VERSION 5.7 ;
BUSBITCHARS "[]" ;
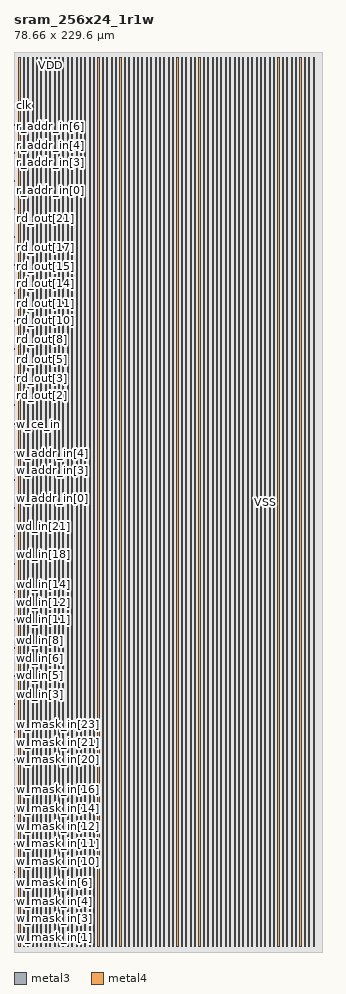
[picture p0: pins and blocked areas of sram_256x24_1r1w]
MACRO sram_256x24_1r1w
  FOREIGN sram_256x24_1r1w 0 0 ;
  SYMMETRY X Y R90 ;
  SIZE 78.660 BY 229.600 ;
  CLASS BLOCK ;
  PIN w_mask_in[0]
    DIRECTION INPUT ;
    USE SIGNAL ;
    SHAPE ABUTMENT ;
    PORT
      LAYER metal3 ;
      RECT 0.000 1.365 0.070 1.435 ;
    END
  END w_mask_in[0]
  PIN w_mask_in[1]
    DIRECTION INPUT ;
    USE SIGNAL ;
    SHAPE ABUTMENT ;
    PORT
      LAYER metal3 ;
      RECT 0.000 3.745 0.070 3.815 ;
    END
  END w_mask_in[1]
  PIN w_mask_in[2]
    DIRECTION INPUT ;
    USE SIGNAL ;
    SHAPE ABUTMENT ;
    PORT
      LAYER metal3 ;
      RECT 0.000 6.125 0.070 6.195 ;
    END
  END w_mask_in[2]
  PIN w_mask_in[3]
    DIRECTION INPUT ;
    USE SIGNAL ;
    SHAPE ABUTMENT ;
    PORT
      LAYER metal3 ;
      RECT 0.000 8.505 0.070 8.575 ;
    END
  END w_mask_in[3]
  PIN w_mask_in[4]
    DIRECTION INPUT ;
    USE SIGNAL ;
    SHAPE ABUTMENT ;
    PORT
      LAYER metal3 ;
      RECT 0.000 10.885 0.070 10.955 ;
    END
  END w_mask_in[4]
  PIN w_mask_in[5]
    DIRECTION INPUT ;
    USE SIGNAL ;
    SHAPE ABUTMENT ;
    PORT
      LAYER metal3 ;
      RECT 0.000 13.265 0.070 13.335 ;
    END
  END w_mask_in[5]
  PIN w_mask_in[6]
    DIRECTION INPUT ;
    USE SIGNAL ;
    SHAPE ABUTMENT ;
    PORT
      LAYER metal3 ;
      RECT 0.000 15.645 0.070 15.715 ;
    END
  END w_mask_in[6]
  PIN w_mask_in[7]
    DIRECTION INPUT ;
    USE SIGNAL ;
    SHAPE ABUTMENT ;
    PORT
      LAYER metal3 ;
      RECT 0.000 18.025 0.070 18.095 ;
    END
  END w_mask_in[7]
  PIN w_mask_in[8]
    DIRECTION INPUT ;
    USE SIGNAL ;
    SHAPE ABUTMENT ;
    PORT
      LAYER metal3 ;
      RECT 0.000 20.405 0.070 20.475 ;
    END
  END w_mask_in[8]
  PIN w_mask_in[9]
    DIRECTION INPUT ;
    USE SIGNAL ;
    SHAPE ABUTMENT ;
    PORT
      LAYER metal3 ;
      RECT 0.000 22.785 0.070 22.855 ;
    END
  END w_mask_in[9]
  PIN w_mask_in[10]
    DIRECTION INPUT ;
    USE SIGNAL ;
    SHAPE ABUTMENT ;
    PORT
      LAYER metal3 ;
      RECT 0.000 25.165 0.070 25.235 ;
    END
  END w_mask_in[10]
  PIN w_mask_in[11]
    DIRECTION INPUT ;
    USE SIGNAL ;
    SHAPE ABUTMENT ;
    PORT
      LAYER metal3 ;
      RECT 0.000 27.545 0.070 27.615 ;
    END
  END w_mask_in[11]
  PIN w_mask_in[12]
    DIRECTION INPUT ;
    USE SIGNAL ;
    SHAPE ABUTMENT ;
    PORT
      LAYER metal3 ;
      RECT 0.000 29.925 0.070 29.995 ;
    END
  END w_mask_in[12]
  PIN w_mask_in[13]
    DIRECTION INPUT ;
    USE SIGNAL ;
    SHAPE ABUTMENT ;
    PORT
      LAYER metal3 ;
      RECT 0.000 32.305 0.070 32.375 ;
    END
  END w_mask_in[13]
  PIN w_mask_in[14]
    DIRECTION INPUT ;
    USE SIGNAL ;
    SHAPE ABUTMENT ;
    PORT
      LAYER metal3 ;
      RECT 0.000 34.685 0.070 34.755 ;
    END
  END w_mask_in[14]
  PIN w_mask_in[15]
    DIRECTION INPUT ;
    USE SIGNAL ;
    SHAPE ABUTMENT ;
    PORT
      LAYER metal3 ;
      RECT 0.000 37.065 0.070 37.135 ;
    END
  END w_mask_in[15]
  PIN w_mask_in[16]
    DIRECTION INPUT ;
    USE SIGNAL ;
    SHAPE ABUTMENT ;
    PORT
      LAYER metal3 ;
      RECT 0.000 39.445 0.070 39.515 ;
    END
  END w_mask_in[16]
  PIN w_mask_in[17]
    DIRECTION INPUT ;
    USE SIGNAL ;
    SHAPE ABUTMENT ;
    PORT
      LAYER metal3 ;
      RECT 0.000 41.825 0.070 41.895 ;
    END
  END w_mask_in[17]
  PIN w_mask_in[18]
    DIRECTION INPUT ;
    USE SIGNAL ;
    SHAPE ABUTMENT ;
    PORT
      LAYER metal3 ;
      RECT 0.000 44.205 0.070 44.275 ;
    END
  END w_mask_in[18]
  PIN w_mask_in[19]
    DIRECTION INPUT ;
    USE SIGNAL ;
    SHAPE ABUTMENT ;
    PORT
      LAYER metal3 ;
      RECT 0.000 46.585 0.070 46.655 ;
    END
  END w_mask_in[19]
  PIN w_mask_in[20]
    DIRECTION INPUT ;
    USE SIGNAL ;
    SHAPE ABUTMENT ;
    PORT
      LAYER metal3 ;
      RECT 0.000 48.965 0.070 49.035 ;
    END
  END w_mask_in[20]
  PIN w_mask_in[21]
    DIRECTION INPUT ;
    USE SIGNAL ;
    SHAPE ABUTMENT ;
    PORT
      LAYER metal3 ;
      RECT 0.000 51.345 0.070 51.415 ;
    END
  END w_mask_in[21]
  PIN w_mask_in[22]
    DIRECTION INPUT ;
    USE SIGNAL ;
    SHAPE ABUTMENT ;
    PORT
      LAYER metal3 ;
      RECT 0.000 53.725 0.070 53.795 ;
    END
  END w_mask_in[22]
  PIN w_mask_in[23]
    DIRECTION INPUT ;
    USE SIGNAL ;
    SHAPE ABUTMENT ;
    PORT
      LAYER metal3 ;
      RECT 0.000 56.105 0.070 56.175 ;
    END
  END w_mask_in[23]
  PIN wd_in[0]
    DIRECTION INPUT ;
    USE SIGNAL ;
    SHAPE ABUTMENT ;
    PORT
      LAYER metal3 ;
      RECT 0.000 58.485 0.070 58.555 ;
    END
  END wd_in[0]
  PIN wd_in[1]
    DIRECTION INPUT ;
    USE SIGNAL ;
    SHAPE ABUTMENT ;
    PORT
      LAYER metal3 ;
      RECT 0.000 60.865 0.070 60.935 ;
    END
  END wd_in[1]
  PIN wd_in[2]
    DIRECTION INPUT ;
    USE SIGNAL ;
    SHAPE ABUTMENT ;
    PORT
      LAYER metal3 ;
      RECT 0.000 63.245 0.070 63.315 ;
    END
  END wd_in[2]
  PIN wd_in[3]
    DIRECTION INPUT ;
    USE SIGNAL ;
    SHAPE ABUTMENT ;
    PORT
      LAYER metal3 ;
      RECT 0.000 65.625 0.070 65.695 ;
    END
  END wd_in[3]
  PIN wd_in[4]
    DIRECTION INPUT ;
    USE SIGNAL ;
    SHAPE ABUTMENT ;
    PORT
      LAYER metal3 ;
      RECT 0.000 68.005 0.070 68.075 ;
    END
  END wd_in[4]
  PIN wd_in[5]
    DIRECTION INPUT ;
    USE SIGNAL ;
    SHAPE ABUTMENT ;
    PORT
      LAYER metal3 ;
      RECT 0.000 70.385 0.070 70.455 ;
    END
  END wd_in[5]
  PIN wd_in[6]
    DIRECTION INPUT ;
    USE SIGNAL ;
    SHAPE ABUTMENT ;
    PORT
      LAYER metal3 ;
      RECT 0.000 72.765 0.070 72.835 ;
    END
  END wd_in[6]
  PIN wd_in[7]
    DIRECTION INPUT ;
    USE SIGNAL ;
    SHAPE ABUTMENT ;
    PORT
      LAYER metal3 ;
      RECT 0.000 75.145 0.070 75.215 ;
    END
  END wd_in[7]
  PIN wd_in[8]
    DIRECTION INPUT ;
    USE SIGNAL ;
    SHAPE ABUTMENT ;
    PORT
      LAYER metal3 ;
      RECT 0.000 77.525 0.070 77.595 ;
    END
  END wd_in[8]
  PIN wd_in[9]
    DIRECTION INPUT ;
    USE SIGNAL ;
    SHAPE ABUTMENT ;
    PORT
      LAYER metal3 ;
      RECT 0.000 79.905 0.070 79.975 ;
    END
  END wd_in[9]
  PIN wd_in[10]
    DIRECTION INPUT ;
    USE SIGNAL ;
    SHAPE ABUTMENT ;
    PORT
      LAYER metal3 ;
      RECT 0.000 82.285 0.070 82.355 ;
    END
  END wd_in[10]
  PIN wd_in[11]
    DIRECTION INPUT ;
    USE SIGNAL ;
    SHAPE ABUTMENT ;
    PORT
      LAYER metal3 ;
      RECT 0.000 84.665 0.070 84.735 ;
    END
  END wd_in[11]
  PIN wd_in[12]
    DIRECTION INPUT ;
    USE SIGNAL ;
    SHAPE ABUTMENT ;
    PORT
      LAYER metal3 ;
      RECT 0.000 87.045 0.070 87.115 ;
    END
  END wd_in[12]
  PIN wd_in[13]
    DIRECTION INPUT ;
    USE SIGNAL ;
    SHAPE ABUTMENT ;
    PORT
      LAYER metal3 ;
      RECT 0.000 89.425 0.070 89.495 ;
    END
  END wd_in[13]
  PIN wd_in[14]
    DIRECTION INPUT ;
    USE SIGNAL ;
    SHAPE ABUTMENT ;
    PORT
      LAYER metal3 ;
      RECT 0.000 91.805 0.070 91.875 ;
    END
  END wd_in[14]
  PIN wd_in[15]
    DIRECTION INPUT ;
    USE SIGNAL ;
    SHAPE ABUTMENT ;
    PORT
      LAYER metal3 ;
      RECT 0.000 94.185 0.070 94.255 ;
    END
  END wd_in[15]
  PIN wd_in[16]
    DIRECTION INPUT ;
    USE SIGNAL ;
    SHAPE ABUTMENT ;
    PORT
      LAYER metal3 ;
      RECT 0.000 96.565 0.070 96.635 ;
    END
  END wd_in[16]
  PIN wd_in[17]
    DIRECTION INPUT ;
    USE SIGNAL ;
    SHAPE ABUTMENT ;
    PORT
      LAYER metal3 ;
      RECT 0.000 98.945 0.070 99.015 ;
    END
  END wd_in[17]
  PIN wd_in[18]
    DIRECTION INPUT ;
    USE SIGNAL ;
    SHAPE ABUTMENT ;
    PORT
      LAYER metal3 ;
      RECT 0.000 101.325 0.070 101.395 ;
    END
  END wd_in[18]
  PIN wd_in[19]
    DIRECTION INPUT ;
    USE SIGNAL ;
    SHAPE ABUTMENT ;
    PORT
      LAYER metal3 ;
      RECT 0.000 103.705 0.070 103.775 ;
    END
  END wd_in[19]
  PIN wd_in[20]
    DIRECTION INPUT ;
    USE SIGNAL ;
    SHAPE ABUTMENT ;
    PORT
      LAYER metal3 ;
      RECT 0.000 106.085 0.070 106.155 ;
    END
  END wd_in[20]
  PIN wd_in[21]
    DIRECTION INPUT ;
    USE SIGNAL ;
    SHAPE ABUTMENT ;
    PORT
      LAYER metal3 ;
      RECT 0.000 108.465 0.070 108.535 ;
    END
  END wd_in[21]
  PIN wd_in[22]
    DIRECTION INPUT ;
    USE SIGNAL ;
    SHAPE ABUTMENT ;
    PORT
      LAYER metal3 ;
      RECT 0.000 110.845 0.070 110.915 ;
    END
  END wd_in[22]
  PIN wd_in[23]
    DIRECTION INPUT ;
    USE SIGNAL ;
    SHAPE ABUTMENT ;
    PORT
      LAYER metal3 ;
      RECT 0.000 113.225 0.070 113.295 ;
    END
  END wd_in[23]
  PIN w_addr_in[0]
    DIRECTION INPUT ;
    USE SIGNAL ;
    SHAPE ABUTMENT ;
    PORT
      LAYER metal3 ;
      RECT 0.000 115.605 0.070 115.675 ;
    END
  END w_addr_in[0]
  PIN w_addr_in[1]
    DIRECTION INPUT ;
    USE SIGNAL ;
    SHAPE ABUTMENT ;
    PORT
      LAYER metal3 ;
      RECT 0.000 117.985 0.070 118.055 ;
    END
  END w_addr_in[1]
  PIN w_addr_in[2]
    DIRECTION INPUT ;
    USE SIGNAL ;
    SHAPE ABUTMENT ;
    PORT
      LAYER metal3 ;
      RECT 0.000 120.365 0.070 120.435 ;
    END
  END w_addr_in[2]
  PIN w_addr_in[3]
    DIRECTION INPUT ;
    USE SIGNAL ;
    SHAPE ABUTMENT ;
    PORT
      LAYER metal3 ;
      RECT 0.000 122.745 0.070 122.815 ;
    END
  END w_addr_in[3]
  PIN w_addr_in[4]
    DIRECTION INPUT ;
    USE SIGNAL ;
    SHAPE ABUTMENT ;
    PORT
      LAYER metal3 ;
      RECT 0.000 125.125 0.070 125.195 ;
    END
  END w_addr_in[4]
  PIN w_addr_in[5]
    DIRECTION INPUT ;
    USE SIGNAL ;
    SHAPE ABUTMENT ;
    PORT
      LAYER metal3 ;
      RECT 0.000 127.505 0.070 127.575 ;
    END
  END w_addr_in[5]
  PIN w_addr_in[6]
    DIRECTION INPUT ;
    USE SIGNAL ;
    SHAPE ABUTMENT ;
    PORT
      LAYER metal3 ;
      RECT 0.000 129.885 0.070 129.955 ;
    END
  END w_addr_in[6]
  PIN w_addr_in[7]
    DIRECTION INPUT ;
    USE SIGNAL ;
    SHAPE ABUTMENT ;
    PORT
      LAYER metal3 ;
      RECT 0.000 132.265 0.070 132.335 ;
    END
  END w_addr_in[7]
  PIN w_ce_in
    DIRECTION INPUT ;
    USE SIGNAL ;
    SHAPE ABUTMENT ;
    PORT
      LAYER metal3 ;
      RECT 0.000 134.645 0.070 134.715 ;
    END
  END w_ce_in
  PIN rd_out[0]
    DIRECTION OUTPUT ;
    USE SIGNAL ;
    SHAPE ABUTMENT ;
    PORT
      LAYER metal3 ;
      RECT 0.000 137.165 0.070 137.235 ;
    END
  END rd_out[0]
  PIN rd_out[1]
    DIRECTION OUTPUT ;
    USE SIGNAL ;
    SHAPE ABUTMENT ;
    PORT
      LAYER metal3 ;
      RECT 0.000 139.545 0.070 139.615 ;
    END
  END rd_out[1]
  PIN rd_out[2]
    DIRECTION OUTPUT ;
    USE SIGNAL ;
    SHAPE ABUTMENT ;
    PORT
      LAYER metal3 ;
      RECT 0.000 141.925 0.070 141.995 ;
    END
  END rd_out[2]
  PIN rd_out[3]
    DIRECTION OUTPUT ;
    USE SIGNAL ;
    SHAPE ABUTMENT ;
    PORT
      LAYER metal3 ;
      RECT 0.000 144.305 0.070 144.375 ;
    END
  END rd_out[3]
  PIN rd_out[4]
    DIRECTION OUTPUT ;
    USE SIGNAL ;
    SHAPE ABUTMENT ;
    PORT
      LAYER metal3 ;
      RECT 0.000 146.685 0.070 146.755 ;
    END
  END rd_out[4]
  PIN rd_out[5]
    DIRECTION OUTPUT ;
    USE SIGNAL ;
    SHAPE ABUTMENT ;
    PORT
      LAYER metal3 ;
      RECT 0.000 149.065 0.070 149.135 ;
    END
  END rd_out[5]
  PIN rd_out[6]
    DIRECTION OUTPUT ;
    USE SIGNAL ;
    SHAPE ABUTMENT ;
    PORT
      LAYER metal3 ;
      RECT 0.000 151.445 0.070 151.515 ;
    END
  END rd_out[6]
  PIN rd_out[7]
    DIRECTION OUTPUT ;
    USE SIGNAL ;
    SHAPE ABUTMENT ;
    PORT
      LAYER metal3 ;
      RECT 0.000 153.825 0.070 153.895 ;
    END
  END rd_out[7]
  PIN rd_out[8]
    DIRECTION OUTPUT ;
    USE SIGNAL ;
    SHAPE ABUTMENT ;
    PORT
      LAYER metal3 ;
      RECT 0.000 156.205 0.070 156.275 ;
    END
  END rd_out[8]
  PIN rd_out[9]
    DIRECTION OUTPUT ;
    USE SIGNAL ;
    SHAPE ABUTMENT ;
    PORT
      LAYER metal3 ;
      RECT 0.000 158.585 0.070 158.655 ;
    END
  END rd_out[9]
  PIN rd_out[10]
    DIRECTION OUTPUT ;
    USE SIGNAL ;
    SHAPE ABUTMENT ;
    PORT
      LAYER metal3 ;
      RECT 0.000 160.965 0.070 161.035 ;
    END
  END rd_out[10]
  PIN rd_out[11]
    DIRECTION OUTPUT ;
    USE SIGNAL ;
    SHAPE ABUTMENT ;
    PORT
      LAYER metal3 ;
      RECT 0.000 163.345 0.070 163.415 ;
    END
  END rd_out[11]
  PIN rd_out[12]
    DIRECTION OUTPUT ;
    USE SIGNAL ;
    SHAPE ABUTMENT ;
    PORT
      LAYER metal3 ;
      RECT 0.000 165.725 0.070 165.795 ;
    END
  END rd_out[12]
  PIN rd_out[13]
    DIRECTION OUTPUT ;
    USE SIGNAL ;
    SHAPE ABUTMENT ;
    PORT
      LAYER metal3 ;
      RECT 0.000 168.105 0.070 168.175 ;
    END
  END rd_out[13]
  PIN rd_out[14]
    DIRECTION OUTPUT ;
    USE SIGNAL ;
    SHAPE ABUTMENT ;
    PORT
      LAYER metal3 ;
      RECT 0.000 170.485 0.070 170.555 ;
    END
  END rd_out[14]
  PIN rd_out[15]
    DIRECTION OUTPUT ;
    USE SIGNAL ;
    SHAPE ABUTMENT ;
    PORT
      LAYER metal3 ;
      RECT 0.000 172.865 0.070 172.935 ;
    END
  END rd_out[15]
  PIN rd_out[16]
    DIRECTION OUTPUT ;
    USE SIGNAL ;
    SHAPE ABUTMENT ;
    PORT
      LAYER metal3 ;
      RECT 0.000 175.245 0.070 175.315 ;
    END
  END rd_out[16]
  PIN rd_out[17]
    DIRECTION OUTPUT ;
    USE SIGNAL ;
    SHAPE ABUTMENT ;
    PORT
      LAYER metal3 ;
      RECT 0.000 177.625 0.070 177.695 ;
    END
  END rd_out[17]
  PIN rd_out[18]
    DIRECTION OUTPUT ;
    USE SIGNAL ;
    SHAPE ABUTMENT ;
    PORT
      LAYER metal3 ;
      RECT 0.000 180.005 0.070 180.075 ;
    END
  END rd_out[18]
  PIN rd_out[19]
    DIRECTION OUTPUT ;
    USE SIGNAL ;
    SHAPE ABUTMENT ;
    PORT
      LAYER metal3 ;
      RECT 0.000 182.385 0.070 182.455 ;
    END
  END rd_out[19]
  PIN rd_out[20]
    DIRECTION OUTPUT ;
    USE SIGNAL ;
    SHAPE ABUTMENT ;
    PORT
      LAYER metal3 ;
      RECT 0.000 184.765 0.070 184.835 ;
    END
  END rd_out[20]
  PIN rd_out[21]
    DIRECTION OUTPUT ;
    USE SIGNAL ;
    SHAPE ABUTMENT ;
    PORT
      LAYER metal3 ;
      RECT 0.000 187.145 0.070 187.215 ;
    END
  END rd_out[21]
  PIN rd_out[22]
    DIRECTION OUTPUT ;
    USE SIGNAL ;
    SHAPE ABUTMENT ;
    PORT
      LAYER metal3 ;
      RECT 0.000 189.525 0.070 189.595 ;
    END
  END rd_out[22]
  PIN rd_out[23]
    DIRECTION OUTPUT ;
    USE SIGNAL ;
    SHAPE ABUTMENT ;
    PORT
      LAYER metal3 ;
      RECT 0.000 191.905 0.070 191.975 ;
    END
  END rd_out[23]
  PIN r_addr_in[0]
    DIRECTION INPUT ;
    USE SIGNAL ;
    SHAPE ABUTMENT ;
    PORT
      LAYER metal3 ;
      RECT 0.000 194.285 0.070 194.355 ;
    END
  END r_addr_in[0]
  PIN r_addr_in[1]
    DIRECTION INPUT ;
    USE SIGNAL ;
    SHAPE ABUTMENT ;
    PORT
      LAYER metal3 ;
      RECT 0.000 196.665 0.070 196.735 ;
    END
  END r_addr_in[1]
  PIN r_addr_in[2]
    DIRECTION INPUT ;
    USE SIGNAL ;
    SHAPE ABUTMENT ;
    PORT
      LAYER metal3 ;
      RECT 0.000 199.045 0.070 199.115 ;
    END
  END r_addr_in[2]
  PIN r_addr_in[3]
    DIRECTION INPUT ;
    USE SIGNAL ;
    SHAPE ABUTMENT ;
    PORT
      LAYER metal3 ;
      RECT 0.000 201.425 0.070 201.495 ;
    END
  END r_addr_in[3]
  PIN r_addr_in[4]
    DIRECTION INPUT ;
    USE SIGNAL ;
    SHAPE ABUTMENT ;
    PORT
      LAYER metal3 ;
      RECT 0.000 203.805 0.070 203.875 ;
    END
  END r_addr_in[4]
  PIN r_addr_in[5]
    DIRECTION INPUT ;
    USE SIGNAL ;
    SHAPE ABUTMENT ;
    PORT
      LAYER metal3 ;
      RECT 0.000 206.185 0.070 206.255 ;
    END
  END r_addr_in[5]
  PIN r_addr_in[6]
    DIRECTION INPUT ;
    USE SIGNAL ;
    SHAPE ABUTMENT ;
    PORT
      LAYER metal3 ;
      RECT 0.000 208.565 0.070 208.635 ;
    END
  END r_addr_in[6]
  PIN r_addr_in[7]
    DIRECTION INPUT ;
    USE SIGNAL ;
    SHAPE ABUTMENT ;
    PORT
      LAYER metal3 ;
      RECT 0.000 210.945 0.070 211.015 ;
    END
  END r_addr_in[7]
  PIN r_ce_in
    DIRECTION INPUT ;
    USE SIGNAL ;
    SHAPE ABUTMENT ;
    PORT
      LAYER metal3 ;
      RECT 0.000 213.325 0.070 213.395 ;
    END
  END r_ce_in
  PIN clk
    DIRECTION INPUT ;
    USE SIGNAL ;
    SHAPE ABUTMENT ;
    PORT
      LAYER metal3 ;
      RECT 0.000 215.845 0.070 215.915 ;
    END
  END clk
  PIN VSS
    DIRECTION INOUT ;
    USE GROUND ;
    PORT
      LAYER metal4 ;
      RECT 1.260 1.400 1.540 228.200 ;
      RECT 3.500 1.400 3.780 228.200 ;
      RECT 5.740 1.400 6.020 228.200 ;
      RECT 7.980 1.400 8.260 228.200 ;
      RECT 10.220 1.400 10.500 228.200 ;
      RECT 12.460 1.400 12.740 228.200 ;
      RECT 14.700 1.400 14.980 228.200 ;
      RECT 16.940 1.400 17.220 228.200 ;
      RECT 19.180 1.400 19.460 228.200 ;
      RECT 21.420 1.400 21.700 228.200 ;
      RECT 23.660 1.400 23.940 228.200 ;
      RECT 25.900 1.400 26.180 228.200 ;
      RECT 28.140 1.400 28.420 228.200 ;
      RECT 30.380 1.400 30.660 228.200 ;
      RECT 32.620 1.400 32.900 228.200 ;
      RECT 34.860 1.400 35.140 228.200 ;
      RECT 37.100 1.400 37.380 228.200 ;
      RECT 39.340 1.400 39.620 228.200 ;
      RECT 41.580 1.400 41.860 228.200 ;
      RECT 43.820 1.400 44.100 228.200 ;
      RECT 46.060 1.400 46.340 228.200 ;
      RECT 48.300 1.400 48.580 228.200 ;
      RECT 50.540 1.400 50.820 228.200 ;
      RECT 52.780 1.400 53.060 228.200 ;
      RECT 55.020 1.400 55.300 228.200 ;
      RECT 57.260 1.400 57.540 228.200 ;
      RECT 59.500 1.400 59.780 228.200 ;
      RECT 61.740 1.400 62.020 228.200 ;
      RECT 63.980 1.400 64.260 228.200 ;
      RECT 66.220 1.400 66.500 228.200 ;
      RECT 68.460 1.400 68.740 228.200 ;
      RECT 70.700 1.400 70.980 228.200 ;
      RECT 72.940 1.400 73.220 228.200 ;
      RECT 75.180 1.400 75.460 228.200 ;
    END
  END VSS
  PIN VDD
    DIRECTION INOUT ;
    USE POWER ;
    PORT
      LAYER metal4 ;
      RECT 2.380 1.400 2.660 228.200 ;
      RECT 4.620 1.400 4.900 228.200 ;
      RECT 6.860 1.400 7.140 228.200 ;
      RECT 9.100 1.400 9.380 228.200 ;
      RECT 11.340 1.400 11.620 228.200 ;
      RECT 13.580 1.400 13.860 228.200 ;
      RECT 15.820 1.400 16.100 228.200 ;
      RECT 18.060 1.400 18.340 228.200 ;
      RECT 20.300 1.400 20.580 228.200 ;
      RECT 22.540 1.400 22.820 228.200 ;
      RECT 24.780 1.400 25.060 228.200 ;
      RECT 27.020 1.400 27.300 228.200 ;
      RECT 29.260 1.400 29.540 228.200 ;
      RECT 31.500 1.400 31.780 228.200 ;
      RECT 33.740 1.400 34.020 228.200 ;
      RECT 35.980 1.400 36.260 228.200 ;
      RECT 38.220 1.400 38.500 228.200 ;
      RECT 40.460 1.400 40.740 228.200 ;
      RECT 42.700 1.400 42.980 228.200 ;
      RECT 44.940 1.400 45.220 228.200 ;
      RECT 47.180 1.400 47.460 228.200 ;
      RECT 49.420 1.400 49.700 228.200 ;
      RECT 51.660 1.400 51.940 228.200 ;
      RECT 53.900 1.400 54.180 228.200 ;
      RECT 56.140 1.400 56.420 228.200 ;
      RECT 58.380 1.400 58.660 228.200 ;
      RECT 60.620 1.400 60.900 228.200 ;
      RECT 62.860 1.400 63.140 228.200 ;
      RECT 65.100 1.400 65.380 228.200 ;
      RECT 67.340 1.400 67.620 228.200 ;
      RECT 69.580 1.400 69.860 228.200 ;
      RECT 71.820 1.400 72.100 228.200 ;
      RECT 74.060 1.400 74.340 228.200 ;
      RECT 76.300 1.400 76.580 228.200 ;
    END
  END VDD
  OBS
    LAYER metal1 ;
    RECT 0 0 78.660 229.600 ;
    LAYER metal2 ;
    RECT 0 0 78.660 229.600 ;
    LAYER metal3 ;
    RECT 0.070 0 78.660 229.600 ;
    RECT 0 0.000 0.070 1.365 ;
    RECT 0 1.435 0.070 3.745 ;
    RECT 0 3.815 0.070 6.125 ;
    RECT 0 6.195 0.070 8.505 ;
    RECT 0 8.575 0.070 10.885 ;
    RECT 0 10.955 0.070 13.265 ;
    RECT 0 13.335 0.070 15.645 ;
    RECT 0 15.715 0.070 18.025 ;
    RECT 0 18.095 0.070 20.405 ;
    RECT 0 20.475 0.070 22.785 ;
    RECT 0 22.855 0.070 25.165 ;
    RECT 0 25.235 0.070 27.545 ;
    RECT 0 27.615 0.070 29.925 ;
    RECT 0 29.995 0.070 32.305 ;
    RECT 0 32.375 0.070 34.685 ;
    RECT 0 34.755 0.070 37.065 ;
    RECT 0 37.135 0.070 39.445 ;
    RECT 0 39.515 0.070 41.825 ;
    RECT 0 41.895 0.070 44.205 ;
    RECT 0 44.275 0.070 46.585 ;
    RECT 0 46.655 0.070 48.965 ;
    RECT 0 49.035 0.070 51.345 ;
    RECT 0 51.415 0.070 53.725 ;
    RECT 0 53.795 0.070 56.105 ;
    RECT 0 56.175 0.070 58.485 ;
    RECT 0 58.555 0.070 60.865 ;
    RECT 0 60.935 0.070 63.245 ;
    RECT 0 63.315 0.070 65.625 ;
    RECT 0 65.695 0.070 68.005 ;
    RECT 0 68.075 0.070 70.385 ;
    RECT 0 70.455 0.070 72.765 ;
    RECT 0 72.835 0.070 75.145 ;
    RECT 0 75.215 0.070 77.525 ;
    RECT 0 77.595 0.070 79.905 ;
    RECT 0 79.975 0.070 82.285 ;
    RECT 0 82.355 0.070 84.665 ;
    RECT 0 84.735 0.070 87.045 ;
    RECT 0 87.115 0.070 89.425 ;
    RECT 0 89.495 0.070 91.805 ;
    RECT 0 91.875 0.070 94.185 ;
    RECT 0 94.255 0.070 96.565 ;
    RECT 0 96.635 0.070 98.945 ;
    RECT 0 99.015 0.070 101.325 ;
    RECT 0 101.395 0.070 103.705 ;
    RECT 0 103.775 0.070 106.085 ;
    RECT 0 106.155 0.070 108.465 ;
    RECT 0 108.535 0.070 110.845 ;
    RECT 0 110.915 0.070 113.225 ;
    RECT 0 113.295 0.070 115.605 ;
    RECT 0 115.675 0.070 117.985 ;
    RECT 0 118.055 0.070 120.365 ;
    RECT 0 120.435 0.070 122.745 ;
    RECT 0 122.815 0.070 125.125 ;
    RECT 0 125.195 0.070 127.505 ;
    RECT 0 127.575 0.070 129.885 ;
    RECT 0 129.955 0.070 132.265 ;
    RECT 0 132.335 0.070 134.645 ;
    RECT 0 134.715 0.070 137.165 ;
    RECT 0 137.235 0.070 139.545 ;
    RECT 0 139.615 0.070 141.925 ;
    RECT 0 141.995 0.070 144.305 ;
    RECT 0 144.375 0.070 146.685 ;
    RECT 0 146.755 0.070 149.065 ;
    RECT 0 149.135 0.070 151.445 ;
    RECT 0 151.515 0.070 153.825 ;
    RECT 0 153.895 0.070 156.205 ;
    RECT 0 156.275 0.070 158.585 ;
    RECT 0 158.655 0.070 160.965 ;
    RECT 0 161.035 0.070 163.345 ;
    RECT 0 163.415 0.070 165.725 ;
    RECT 0 165.795 0.070 168.105 ;
    RECT 0 168.175 0.070 170.485 ;
    RECT 0 170.555 0.070 172.865 ;
    RECT 0 172.935 0.070 175.245 ;
    RECT 0 175.315 0.070 177.625 ;
    RECT 0 177.695 0.070 180.005 ;
    RECT 0 180.075 0.070 182.385 ;
    RECT 0 182.455 0.070 184.765 ;
    RECT 0 184.835 0.070 187.145 ;
    RECT 0 187.215 0.070 189.525 ;
    RECT 0 189.595 0.070 191.905 ;
    RECT 0 191.975 0.070 194.285 ;
    RECT 0 194.355 0.070 196.665 ;
    RECT 0 196.735 0.070 199.045 ;
    RECT 0 199.115 0.070 201.425 ;
    RECT 0 201.495 0.070 203.805 ;
    RECT 0 203.875 0.070 206.185 ;
    RECT 0 206.255 0.070 208.565 ;
    RECT 0 208.635 0.070 210.945 ;
    RECT 0 211.015 0.070 213.325 ;
    RECT 0 213.395 0.070 215.845 ;
    RECT 0 215.915 0.070 229.600 ;
    LAYER metal4 ;
    RECT 0 0 78.660 1.400 ;
    RECT 0 228.200 78.660 229.600 ;
    RECT 0.000 1.400 1.260 228.200 ;
    RECT 1.540 1.400 2.380 228.200 ;
    RECT 2.660 1.400 3.500 228.200 ;
    RECT 3.780 1.400 4.620 228.200 ;
    RECT 4.900 1.400 5.740 228.200 ;
    RECT 6.020 1.400 6.860 228.200 ;
    RECT 7.140 1.400 7.980 228.200 ;
    RECT 8.260 1.400 9.100 228.200 ;
    RECT 9.380 1.400 10.220 228.200 ;
    RECT 10.500 1.400 11.340 228.200 ;
    RECT 11.620 1.400 12.460 228.200 ;
    RECT 12.740 1.400 13.580 228.200 ;
    RECT 13.860 1.400 14.700 228.200 ;
    RECT 14.980 1.400 15.820 228.200 ;
    RECT 16.100 1.400 16.940 228.200 ;
    RECT 17.220 1.400 18.060 228.200 ;
    RECT 18.340 1.400 19.180 228.200 ;
    RECT 19.460 1.400 20.300 228.200 ;
    RECT 20.580 1.400 21.420 228.200 ;
    RECT 21.700 1.400 22.540 228.200 ;
    RECT 22.820 1.400 23.660 228.200 ;
    RECT 23.940 1.400 24.780 228.200 ;
    RECT 25.060 1.400 25.900 228.200 ;
    RECT 26.180 1.400 27.020 228.200 ;
    RECT 27.300 1.400 28.140 228.200 ;
    RECT 28.420 1.400 29.260 228.200 ;
    RECT 29.540 1.400 30.380 228.200 ;
    RECT 30.660 1.400 31.500 228.200 ;
    RECT 31.780 1.400 32.620 228.200 ;
    RECT 32.900 1.400 33.740 228.200 ;
    RECT 34.020 1.400 34.860 228.200 ;
    RECT 35.140 1.400 35.980 228.200 ;
    RECT 36.260 1.400 37.100 228.200 ;
    RECT 37.380 1.400 38.220 228.200 ;
    RECT 38.500 1.400 39.340 228.200 ;
    RECT 39.620 1.400 40.460 228.200 ;
    RECT 40.740 1.400 41.580 228.200 ;
    RECT 41.860 1.400 42.700 228.200 ;
    RECT 42.980 1.400 43.820 228.200 ;
    RECT 44.100 1.400 44.940 228.200 ;
    RECT 45.220 1.400 46.060 228.200 ;
    RECT 46.340 1.400 47.180 228.200 ;
    RECT 47.460 1.400 48.300 228.200 ;
    RECT 48.580 1.400 49.420 228.200 ;
    RECT 49.700 1.400 50.540 228.200 ;
    RECT 50.820 1.400 51.660 228.200 ;
    RECT 51.940 1.400 52.780 228.200 ;
    RECT 53.060 1.400 53.900 228.200 ;
    RECT 54.180 1.400 55.020 228.200 ;
    RECT 55.300 1.400 56.140 228.200 ;
    RECT 56.420 1.400 57.260 228.200 ;
    RECT 57.540 1.400 58.380 228.200 ;
    RECT 58.660 1.400 59.500 228.200 ;
    RECT 59.780 1.400 60.620 228.200 ;
    RECT 60.900 1.400 61.740 228.200 ;
    RECT 62.020 1.400 62.860 228.200 ;
    RECT 63.140 1.400 63.980 228.200 ;
    RECT 64.260 1.400 65.100 228.200 ;
    RECT 65.380 1.400 66.220 228.200 ;
    RECT 66.500 1.400 67.340 228.200 ;
    RECT 67.620 1.400 68.460 228.200 ;
    RECT 68.740 1.400 69.580 228.200 ;
    RECT 69.860 1.400 70.700 228.200 ;
    RECT 70.980 1.400 71.820 228.200 ;
    RECT 72.100 1.400 72.940 228.200 ;
    RECT 73.220 1.400 74.060 228.200 ;
    RECT 74.340 1.400 75.180 228.200 ;
    RECT 75.460 1.400 76.300 228.200 ;
    RECT 76.580 1.400 78.660 228.200 ;
    LAYER OVERLAP ;
    RECT 0 0 78.660 229.600 ;
  END
END sram_256x24_1r1w

END LIBRARY
